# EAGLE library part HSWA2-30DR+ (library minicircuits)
SPDT RF SWITCH Absorptive RF Switch with internal driver Source: http://www.minicircuits.com .. HSWA2-30DR+.pdf

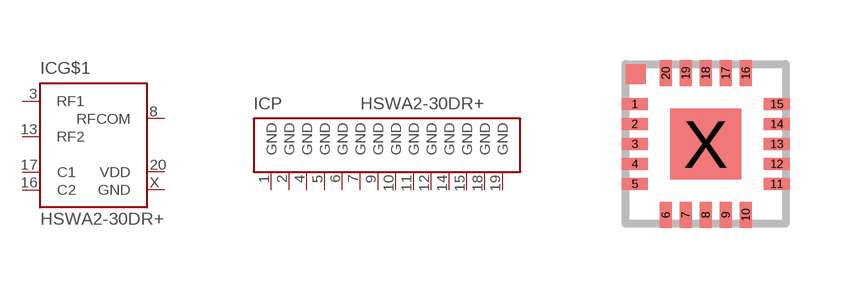
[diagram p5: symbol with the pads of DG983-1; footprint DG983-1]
Designator prefix IC; gates G$1=HSWA2-30DR+ P=GND14

## HSWA2-30DR+ (OC_FARNELL: unknown; OC_NEWARK: unknown)  [DG983-1]
1  P:GND  pwr
2  P:GND  pwr
3  G$1:RF1  pas
4  P:GND  pwr
5  P:GND  pwr
6  P:GND  pwr
7  P:GND  pwr
8  G$1:RFCOM  pas
9  P:GND  pwr
10  P:GND  pwr
11  P:GND  pwr
12  P:GND  pwr
13  G$1:RF2  pas
14  P:GND  pwr
15  P:GND  pwr
16  G$1:C2  pas
17  G$1:C1  pas
18  P:GND  pwr
19  P:GND  pwr
20  G$1:VDD  in
X  G$1:GND  pwr

## Footprint DG983-1 (pad centres in mm)
DG983-1 Source: http://www.minicircuits.com .. HSWA2-30DR+.pdf
smd 0.66 x 0.31: 1 -1.775,1; 2 -1.775,0.5; 3 -1.775,0; 4 -1.775,-0.5; 5 -1.775,-1; 11 1.775,-1; 12 1.775,-0.5; 13 1.775,0; 14 1.775,0.5; 15 1.775,1
smd 0.31 x 0.66: 6 -1,-1.775; 7 -0.5,-1.775; 8 0,-1.775; 9 0.5,-1.775; 10 1,-1.775; 16 1,1.775; 17 0.5,1.775; 18 0,1.775; 19 -0.5,1.775; 20 -1,1.775
smd 1.78 x 1.78: X 0,0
